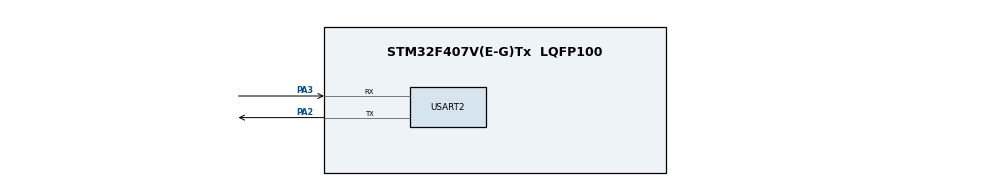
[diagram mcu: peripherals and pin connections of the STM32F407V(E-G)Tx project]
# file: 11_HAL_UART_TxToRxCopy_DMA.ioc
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Dma.Request0=USART2_TX
Dma.Request1=USART2_RX
Dma.USART2_RX.1.Direction=DMA_PERIPH_TO_MEMORY
Dma.USART2_RX.1.FIFOMode=DMA_FIFOMODE_DISABLE
Dma.USART2_RX.1.Instance=DMA1_Stream5
Dma.USART2_RX.1.MemDataAlignment=DMA_MDATAALIGN_BYTE
Dma.USART2_RX.1.MemInc=DMA_MINC_ENABLE
Dma.USART2_RX.1.Mode=DMA_NORMAL
Dma.USART2_RX.1.PeriphDataAlignment=DMA_PDATAALIGN_BYTE
Dma.USART2_RX.1.PeriphInc=DMA_PINC_DISABLE
Dma.USART2_RX.1.Priority=DMA_PRIORITY_LOW
Dma.USART2_TX.0.Direction=DMA_MEMORY_TO_PERIPH
Dma.USART2_TX.0.FIFOMode=DMA_FIFOMODE_DISABLE
Dma.USART2_TX.0.Instance=DMA1_Stream6
Dma.USART2_TX.0.MemDataAlignment=DMA_MDATAALIGN_BYTE
Dma.USART2_TX.0.MemInc=DMA_MINC_ENABLE
Dma.USART2_TX.0.Mode=DMA_NORMAL
Dma.USART2_TX.0.PeriphDataAlignment=DMA_PDATAALIGN_BYTE
Dma.USART2_TX.0.PeriphInc=DMA_PINC_DISABLE
Dma.USART2_TX.0.Priority=DMA_PRIORITY_LOW
Mcu.Family=STM32F4
Mcu.Name=STM32F407V(E-G)Tx
Mcu.Package=LQFP100
NVIC.DMA1_Stream5_IRQn=true\:0\:0\:false\:false\:true\:false\:true\:true
NVIC.DMA1_Stream6_IRQn=true\:0\:0\:false\:false\:true\:false\:true\:true
NVIC.PriorityGroup=NVIC_PRIORITYGROUP_0
NVIC.USART2_IRQn=true\:0\:0\:false\:false\:true\:true\:true\:true
PA2.Mode=Asynchronous
PA2.Signal=USART2_TX
PA3.Mode=Asynchronous
PA3.Signal=USART2_RX
PH0-OSC_IN.Mode=HSE-External-Oscillator
PH0-OSC_IN.Signal=RCC_OSC_IN
PH1-OSC_OUT.Mode=HSE-External-Oscillator
PH1-OSC_OUT.Signal=RCC_OSC_OUT
ProjectManager.HeapSize=0x200
ProjectManager.StackSize=0x400
ProjectManager.TargetToolchain=STM32CubeIDE
RCC.48MHZClocksFreq_Value=48000000
RCC.AHBFreq_Value=168000000
RCC.APB1CLKDivider=RCC_HCLK_DIV4
RCC.APB1Freq_Value=42000000
RCC.APB1TimFreq_Value=84000000
RCC.APB2CLKDivider=RCC_HCLK_DIV2
RCC.APB2Freq_Value=84000000
RCC.APB2TimFreq_Value=168000000
RCC.CortexFreq_Value=168000000
RCC.HCLKFreq_Value=168000000
RCC.HSE_VALUE=8000000
RCC.HSI_VALUE=16000000
RCC.PLLM=8
RCC.PLLN=336
RCC.PLLQ=7
RCC.PLLSourceVirtual=RCC_PLLSOURCE_HSE
RCC.SYSCLKFreq_VALUE=168000000
RCC.SYSCLKSource=RCC_SYSCLKSOURCE_PLLCLK
RCC.VCOOutputFreq_Value=336000000
USART2.VirtualMode=VM_ASYNC
board=STM32F407G-DISC1

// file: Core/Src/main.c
/* USER CODE BEGIN Header */
/**
******************************************************************************
* @file : main.c
* @brief : Main program body
******************************************************************************
*/
/* USER CODE END Header */

#include "main.h"

UART_HandleTypeDef huart2;
DMA_HandleTypeDef hdma_usart2_tx;
DMA_HandleTypeDef hdma_usart2_rx;

/* USER CODE BEGIN PV */
uint8_t rxData[10];
/* USER CODE END PV */

void SystemClock_Config(void);
static void MX_GPIO_Init(void);
static void MX_DMA_Init(void);
static void MX_USART2_UART_Init(void);

int main(void)
{
    HAL_Init();

    SystemClock_Config();

    MX_GPIO_Init();
    MX_DMA_Init();
    MX_USART2_UART_Init();

    /* Start UART DMA Receive */
    HAL_UART_Receive_DMA(&huart2,
                         rxData,
                         7);

    while (1)
    {

    }
}

void SystemClock_Config(void)
{
    RCC_OscInitTypeDef RCC_OscInitStruct = {0};
    RCC_ClkInitTypeDef RCC_ClkInitStruct = {0};

    __HAL_RCC_PWR_CLK_ENABLE();
    __HAL_PWR_VOLTAGESCALING_CONFIG(PWR_REGULATOR_VOLTAGE_SCALE1);

    RCC_OscInitStruct.OscillatorType = RCC_OSCILLATORTYPE_HSI;
    RCC_OscInitStruct.HSIState = RCC_HSI_ON;
    RCC_OscInitStruct.HSICalibrationValue = RCC_HSICALIBRATION_DEFAULT;
    RCC_OscInitStruct.PLL.PLLState = RCC_PLL_ON;
    RCC_OscInitStruct.PLL.PLLSource = RCC_PLLSOURCE_HSI;
    RCC_OscInitStruct.PLL.PLLM = 8;
    RCC_OscInitStruct.PLL.PLLN = 50;
    RCC_OscInitStruct.PLL.PLLP = RCC_PLLP_DIV4;
    RCC_OscInitStruct.PLL.PLLQ = 7;

    if (HAL_RCC_OscConfig(&RCC_OscInitStruct) != HAL_OK)
    {
        Error_Handler();
    }

    RCC_ClkInitStruct.ClockType = RCC_CLOCKTYPE_HCLK |
                                  RCC_CLOCKTYPE_SYSCLK |
                                  RCC_CLOCKTYPE_PCLK1 |
                                  RCC_CLOCKTYPE_PCLK2;

    RCC_ClkInitStruct.SYSCLKSource = RCC_SYSCLKSOURCE_PLLCLK;
    RCC_ClkInitStruct.AHBCLKDivider = RCC_SYSCLK_DIV1;
    RCC_ClkInitStruct.APB1CLKDivider = RCC_HCLK_DIV4;
    RCC_ClkInitStruct.APB2CLKDivider = RCC_HCLK_DIV2;

    if (HAL_RCC_ClockConfig(&RCC_ClkInitStruct,
                            FLASH_LATENCY_0) != HAL_OK)
    {
        Error_Handler();
    }
}

static void MX_USART2_UART_Init(void)
{
    huart2.Instance = USART2;

    huart2.Init.BaudRate = 115200;
    huart2.Init.WordLength = UART_WORDLENGTH_8B;
    huart2.Init.StopBits = UART_STOPBITS_1;
    huart2.Init.Parity = UART_PARITY_NONE;
    huart2.Init.Mode = UART_MODE_TX_RX;
    huart2.Init.HwFlowCtl = UART_HWCONTROL_NONE;
    huart2.Init.OverSampling = UART_OVERSAMPLING_16;

    if (HAL_UART_Init(&huart2) != HAL_OK)
    {
        Error_Handler();
    }
}

static void MX_DMA_Init(void)
{
    __HAL_RCC_DMA1_CLK_ENABLE();

    HAL_NVIC_SetPriority(DMA1_Stream5_IRQn,
                         0,
                         0);

    HAL_NVIC_EnableIRQ(DMA1_Stream5_IRQn);

    HAL_NVIC_SetPriority(DMA1_Stream6_IRQn,
                         0,
                         0);

    HAL_NVIC_EnableIRQ(DMA1_Stream6_IRQn);
}

static void MX_GPIO_Init(void)
{
    GPIO_InitTypeDef GPIO_InitStruct = {0};

    __HAL_RCC_GPIOH_CLK_ENABLE();
    __HAL_RCC_GPIOA_CLK_ENABLE();

    GPIO_InitStruct.Pin = GPIO_PIN_0;
    GPIO_InitStruct.Mode = GPIO_MODE_INPUT;
    GPIO_InitStruct.Pull = GPIO_NOPULL;

    HAL_GPIO_Init(GPIOA,
                  &GPIO_InitStruct);
}

/* UART DMA RX Complete Callback */
void HAL_UART_RxCpltCallback(UART_HandleTypeDef *huart)
{
    if(huart->Instance == USART2)
    {
        HAL_UART_Receive_DMA(&huart2,
                             rxData,
                             7);
    }
}

void Error_Handler(void)
{
    __disable_irq();

    while (1)
    {

    }
}
